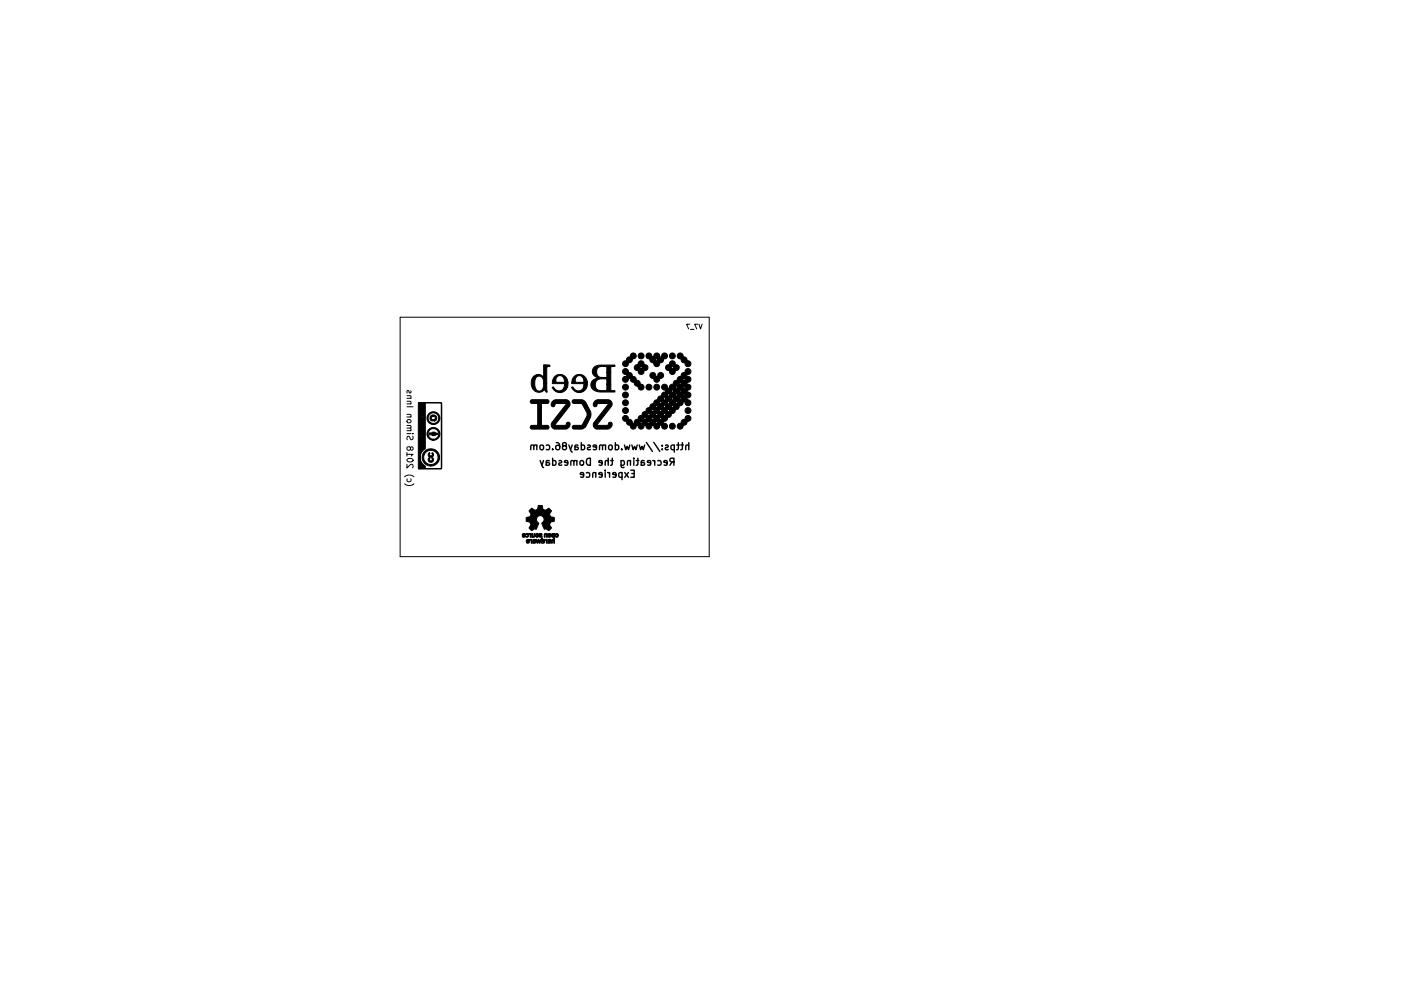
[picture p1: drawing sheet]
<svg xmlns="http://www.w3.org/2000/svg" width="297mm" height="210mm" viewBox="0 0 297 210" stroke-linecap="round" stroke-linejoin="round" font-family="sans-serif">
<g fill="none" stroke="#000" stroke-width=".21">
<path d="M84.8 67.3h65.6v50.8h-65.6zM146.2 68.8h-.6l.4 1M146.4 69.9h.7M148 68.8h-.7l.4 1M148.2 68.8l.3 1 .4-1M86.3 98.5v.8l.9-.8 .4 .2-.1 .5M86.3 96.4h1.3l-.4 .4M86.3 90.8l.8 .1-.1 .5M86.3 90.3h.8v.3l-.1 .2M86.3 87.9l.8 .1-.1 .5M86.3 85.1l.8 .1-.1 .5M86.3 84h.8l-.1 .5"/>
<path d="M86.3 96v.8M86.3 92h.8M86.3 91.4h.8M86.3 88.5h.8M86.3 86.3h1.3M86.3 85.7h.8M86.3 84.5h.8M86.3 97.4a.77 .77 0 0 1 1.3 .3 .74 .74 0 0 1-1.3-.1zM86.3 89.2l.6-.2 .2 .5-.2 .2h-.4l-.2-.2zM87 95l-.2-.2h-.4l-.1 .2 .1 .5h.4l.3-.7 .4 .1v.6h-.2l-.3-.2M87.1 82.9v.3l-.1 .2-.2-.1-.1-.4h-.4v.5M87.5 92h.1"/>
<path d="M87.5 92.6l.1 .5-.1 .1h-.4l-.3-.5-.3-.1-.2 .2v.5M85.8 102.6a1.49 1.49 0 0 0 2 0M85.8 101.2a1.49 1.49 0 0 1 2 0M86.3 101.6v.4l.2 .2 .6-.1v-.5"/>
</g>
<g fill="none" stroke="#000" stroke-width=".3">
<path d="M113.2 94.6l-.2-.2-.4 .1-.1 .9M113.8 94.6l-.2-.2-.3 .1-.1 .9M113.8 94.4v1M114.5 97.7l.5 1.4 .2 .1M114.5 94.6l.3-.2 .4 .2 .1 .5-.2 .2-.3 .1-.3-.1zM115.2 97.7l-.3 1M115.8 98.1h.5l.2 .3-.2 .3-.5-.1M115.8 94.5l.5-.1 .2 .3-.1 .6h-.6M116.5 97.8h-.6l-.1 .9M117.2 97.8l.4-.1 .3 .3-.2 .6h-.5M117.2 97.2v1.5M117.2 95.3v.1"/>
<path d="M118 93.9l.4 .1a1.01 1.01 0 0 1 0 1.4l-.5-.1-.1-.5 .3-.3 .4 .1 .2 .2M118.5 97.8l.4-.1 .2 .2-.1 .2-.5 .2v.3h.6M119.5 94.6l-.2 .2v.3l.2 .3 .5-.1 .1-.5-.1-.2-.7-.2 .1-.4 .4-.1 .2 .2 .1 .2-.3 .3M120.4 98.2l-.7-.1v-.3l.5-.1 .2 .2-.1 .7h-.6M120.6 94.4l.5 1.4 .2 .1M121.3 94.4l-.3 1M121.7 97.9l-.2-.2-.4 .1-.1 .9M121.9 94.8h.5l.2 .3-.2 .3-.5-.1M122.3 97.9l-.2-.2-.4 .1v.9M122.3 97.7v1M122.5 94.5h-.5l-.1 .9M123 97.9l.2-.2 .5 .2v.5l-.1 .2-.4 .1-.2-.1z"/>
<path d="M123.3 94.5l.4-.1 .3 .3-.2 .6h-.5M123.3 93.9v1.5M124.5 97.4l.7-.2v1.5a.78 .78 0 0 1-.8-.4 .78 .78 0 0 1 .1-.9zM124.6 94.5l.4-.1 .2 .2-.1 .2-.5 .2v.3h.6M126.5 94.9l-.7-.1v-.3l.5-.1 .2 .2-.1 .7h-.6M127.7 98.2l-.7-.1v-.3l.5-.1 .2 .2-.1 .7h-.6M127.8 94.6l-.3-.2-.3 .1-.1 .9M128.3 99.8v.1M128.4 94.6l-.2-.2-.4 .1v.9M128.4 94.4v1M129 97.9l-.3-.2-.3 .1-.1 .9M129 97.2v1.5"/>
<path d="M129.1 94.6l.2-.2 .5 .2v.5l-.1 .2-.4 .1-.2-.1zM129.5 97.7h.5M129.8 97.2v1.3l-.3 .2M130.5 94.5l.4-.1 .3 .3-.2 .6h-.5M130.5 93.9v1.5M131.7 97.7v1.2l.3 .3 .3-.1M131.7 97.8l.4-.1 .3 .3-.2 .6h-.5M131.8 95.3v.1M132.4 94.4l.3 1 .3-.7 .3 .7 .2-1M133.7 97.9l-.2-.2-.4 .1-.1 .9M133.7 97.7v1M133.7 99.8h.8v1.5h-.8"/>
<path d="M134 94.4l.3 1 .2-.7 .3 .7 .3-1M134.4 97.2v.2M134.4 97.7v1M134.9 97.7h.6M135.2 97.2v1.3l-.3 .2M135.5 94.4l.3 1 .3-.7 .3 .7 .3-1M136 98.1h.5l.2 .3-.2 .3-.5-.1M136.6 97.8h-.6v.9M137 93.8l1.3 2M138 98.2l-.8-.1 .1-.3 .4-.1 .3 .2-.1 .7h-.6M138.4 97.7l.4 .3M138.6 93.8l1.3 2"/>
<path d="M138.8 97.7v1M139.5 97.8l.4-.1 .3 .3-.2 .6h-.5M140.4 95.3v.1M140.4 94.5v.1M141.1 94.5l.4-.1 .2 .2-.1 .2-.5 .2v.3h.6M141.5 98.2l-.8-.1 .1-.3 .4-.1 .3 .2-.1 .7h-.6M142.5 98l-.5 .7M142.9 98l-.7-.1-.2-.2 .1-.3 .8-.2v1.5M143 94.5l-.5-.1-.2 .3 .1 .6h.6M143 94.4v1.5M143.5 94.4h.5M143.8 93.9v1.3l-.3 .2"/>
<path d="M144.3 94.4h.6M144.7 93.9v1.3l-.4 .2M146 94.6l-.2-.2-.3 .1-.1 .9M146 93.9v1.5M123.7 100.8l-.7-.2 .1-.3h.4l.2 .2v.7h-.6M124.3 100.3h.4l.3 .2-.1 .7h-.6M126.3 100.4l-.2-.1h-.4v1M126.3 100.3v1M127.7 100.8l-.7-.2v-.3h.5l.2 .2-.1 .7h-.6M128.3 100.3v1M128.8 100.3l.4 .2M129.2 100.3v1"/>
<path d="M130.6 100.8l-.7-.2 .1-.3h.4l.2 .2-.1 .7h-.5M131.9 100.3h-.4l-.3 .2 .1 .7h.6M131.9 100.3v1.5M132.5 100.3l.7 1M133.2 100.3l-.7 1M134 100.5h.5"/>
</g>
<g fill="#000" stroke="#000" stroke-width=".21">
<path d="M115.3 77.4l1.3 .1v.2l-.5 .1-.2 .3v3.3h-.6v-.3a.96 .96 0 0 0-.5-1.1 .96 .96 0 0 0-1.1 .1 2.25 2.25 0 0 0 .4 2.8l.3 .1a1.25 1.25 0 0 0 .9-1.6h.6l.1 1.8h-.1l-.5-.5a1.66 1.66 0 0 1-2 .3 1.66 1.66 0 0 1-.8-2 1.44 1.44 0 0 1 1-1.5 1.44 1.44 0 0 1 1.7 .6zM117.6 79.9l1-.4a1.69 1.69 0 0 1 1.8 1.6h-.7v-.1a.96 .96 0 0 0-.5-1.2 .96 .96 0 0 0-1.2 .2 .6 .6 0 0 0 .1 1.1h2.3a1.71 1.71 0 0 1-1.1 2.1 1.71 1.71 0 0 1-2.1-1.1h.2a1.23 1.23 0 0 0 1.5 .8 1.23 1.23 0 0 0 .8-1.5h-2.6l.1-.9zM121.7 79.9l1-.4a1.69 1.69 0 0 1 1.8 1.6h-.7v-.1a.96 .96 0 0 0-.4-1.2 .96 .96 0 0 0-1.2 .2 .6 .6 0 0 0 0 1.1h2.3a1.71 1.71 0 0 1-1.1 2.1 1.71 1.71 0 0 1-2.1-1.1h.2a1.23 1.23 0 0 0 1.5 .8 1.23 1.23 0 0 0 .8-1.5h-2.6l.2-.9zM126 77.9l1-.4h3.4v.2l-.9 .2v1.1h-.8l-.2-1.2h-1a1.2 1.2 0 0 0-1 1.4 1.2 1.2 0 0 0 1.6 .9h.6v-1.1h.8v2.5h-.8v-1.1h-1.4a1.3 1.3 0 0 0-1.1 1.6 1.3 1.3 0 0 0 1.7 .9h.4a.59 .59 0 0 0 .4-.9v-.5h.8v1.2l.9 .2v.3l-3.4-.1a1.49 1.49 0 0 1-1.5-.7 1.49 1.49 0 0 1 .1-1.6l1.2-.7a1.31 1.31 0 0 1-1.1-.8 1.31 1.31 0 0 1 .3-1.4zM132.2 78.4l.7-.2 .2 .2 .1 .4a.18 .18 0 0 0 0 .3 .18 .18 0 0 0 .3-.1l.4 .3 .2 .4a.17 .17 0 0 0 0 .2 .17 .17 0 0 0 .2 0l.5 .3v.5l.6 .1 .3 .5a.18 .18 0 0 0 0 .3 .18 .18 0 0 0 .3-.1h.1a.62 .62 0 0 1 .4 .8 .62 .62 0 0 1-.8 .4 .62 .62 0 0 1-.3-.8l-.7-.1-.2-.3v-.4l-.5-.1-.3-.5a.18 .18 0 0 0-.1-.3 .18 .18 0 0 0-.2 .1l-.2-.1v.5l-.4 .4h-.3l-.4-.3-.1-.4 .2-.4 .3-.1h.4v-.5h-.5l-.4-.3zM133 75.9l.4-.2a.18 .18 0 0 0 .3 0 .18 .18 0 0 0 0-.3l.1-.3 .3-.2 .6 .2 .1 .7-.2 .3h-.3a.18 .18 0 0 0-.3 0 .18 .18 0 0 0 .1 .3l-.2 .4-.4 .2a.2 .2 0 0 0-.3-.1 .2 .2 0 0 0 0 .3 .62 .62 0 0 1-.7 .6 .62 .62 0 0 1-.5-.8 .62 .62 0 0 1 .9-.4l-.1-.4zM134.7 77.6l.4-.2a.18 .18 0 0 0 .3 0 .18 .18 0 0 0-.1-.3l.2-.4 .5-.1 .4 .2 .1 .4a.18 .18 0 0 0 .1 .3 .18 .18 0 0 0 .2-.1l.5 .3-1.4 .1a.18 .18 0 0 0-.3 0 .18 .18 0 0 0 .1 .3v.2h.5v-.6h1.1v.6l-.5 .3a.2 .2 0 0 0-.3 0 .2 .2 0 0 0 0 .3 .62 .62 0 0 1-.7 .5 .62 .62 0 0 1-.4-.8h-.5l-.3-.2-.1-.5zM137.1 75.1l.7-.2 .3 .2 .1 .4a.18 .18 0 0 0 0 .3 .18 .18 0 0 0 .3-.1l.2 .1v-.6l.4-.3 .5 .1 .3 .5a.18 .18 0 0 0 0 .3 .18 .18 0 0 0 .2-.1l.2 .1v-.5l.4-.4 .5 .1 .3 .4-.1 .4-.4 .3h-1.8a.18 .18 0 0 0-.2 0 .18 .18 0 0 0 0 .3v.2h.5v-.5h1.1v.6l-.5 .3a.18 .18 0 0 0-.3-.1 .18 .18 0 0 0 .1 .3 .62 .62 0 0 1-.8 .6 .62 .62 0 0 1-.4-.9h-.6l-.3-.4v-.4h-.4l-.3-.2-.1-.5zM138 79.2l.6-.1 .3 .2 .1 .4a.18 .18 0 0 0 0 .2 .18 .18 0 0 0 .3 0h.2v-.4l.2-.3 .7-.1 .2 .3 .1 .4-.2 .3-.4 .2a.2 .2 0 0 0-.3-.1 .21 .21 0 0 0 .1 .4 .62 .62 0 0 1-.8 .5 .62 .62 0 0 1-.4-.9l-.4 .1-.4-.3-.1-.4zM142.1 76.7l.7-.1 .3 .3 .1 .3a.18 .18 0 0 0 0 .3 .18 .18 0 0 0 .3-.1l.4 .3-1.3 .1a.18 .18 0 0 0-.3 0 .18 .18 0 0 0 0 .3v.2h.5v-.6h1.1v.6l-.4 .3a.2 .2 0 0 0-.4 0 .2 .2 0 0 0 .1 .3 .62 .62 0 0 1-.8 .5 .62 .62 0 0 1-.4-.8l-.6-.1-.3-.4 .1-.5 .5-.2a.18 .18 0 0 0 .3 0 .18 .18 0 0 0-.1-.3zM143.8 75.1l.6-.2 .3 .2 .1 .4a.18 .18 0 0 0 0 .3 .18 .18 0 0 0 .3-.1l.4 .3 .2 .3a.18 .18 0 0 0 0 .3 .18 .18 0 0 0 .2 0h.1a.62 .62 0 0 1 .5 .7 .62 .62 0 0 1-.9 .5 .62 .62 0 0 1-.3-.9h-.6l-.3-.6a.18 .18 0 0 0 0-.2 .18 .18 0 0 0-.3 0l-.3-.1-.2-.3zM132.2 88.3l.7-.1 .2 .2 .1 .4a.18 .18 0 0 0 0 .2 .18 .18 0 0 0 .3 0l.4 .2 .2 .4a.18 .18 0 0 0 0 .3 .18 .18 0 0 0 .2-.1l.2 .1v-.4l.2-.3 .3-.2h.4v-.5l.5-.4a.18 .18 0 0 0 .3 0 .18 .18 0 0 0-.1-.2l.3-.5 .4-.1a.18 .18 0 0 0 .2 0 .18 .18 0 0 0 0-.3l.2-.4 .4-.1a.18 .18 0 0 0 .3 0 .18 .18 0 0 0-.1-.3l.2-.4 .4-.1a.18 .18 0 0 0 .3-.1 .18 .18 0 0 0-.1-.2l.2-.4 .4-.2a.18 .18 0 0 0 .3 0 .18 .18 0 0 0 0-.3l.1-.3 .5-.2a.18 .18 0 0 0 .2 0 .18 .18 0 0 0 0-.3l.2-.4 .4-.1a.18 .18 0 0 0 .3 0 .18 .18 0 0 0-.1-.3l.1-.2h-.5l-.3-.3-.1-.4 .2-.3 .6-.1 .4 .3v.5h.5v-.6l.6-.3a.18 .18 0 0 0 .2 0 .18 .18 0 0 0 0-.3l.2-.4 .4-.1a.18 .18 0 0 0 .3 0 .18 .18 0 0 0-.1-.3l.2-.4 .4-.1a.18 .18 0 0 0 .3-.1 .18 .18 0 0 0-.1-.2l.2-.4 .4-.2a.18 .18 0 0 0 .3 0 .18 .18 0 0 0-.1-.3l.2-.3 .3-.2 .6 .2 .1 .7-.2 .3h-.3a.18 .18 0 0 0-.3 .1 .18 .18 0 0 0 .1 .2l-.1 .2h.5l.3 .3-1.4 .1a.18 .18 0 0 0-.2 0 .18 .18 0 0 0 0 .3v.1h.5v-.5h1.1l.1 .2-.1 .4-.4 .3h-2.1v.5h.6v-.5h1.1v.5h.5l.3 .3h-3a.18 .18 0 0 0-.3 0 .18 .18 0 0 0 .1 .3l-.1 .2h.5v-.5h1.2v.2a.18 .18 0 0 0 0 .3 .18 .18 0 0 0 .3 0h.2v-.5l1.2 .1-.1 .5-.4 .2h-3.7v.5h.5v-.5h1.1v.5h.6v-.5h1.1v.5h.5l.3 .3h-4.9v.6h.5v-.6h1.1v.6h.5v-.6h1.2v.6h.5v-.6h1.1l.1 .4-.3 .4-5.3 .1a.18 .18 0 0 0-.3 0 .18 .18 0 0 0 .1 .3l-.1 .2h.6v-.5h1.1v.2a.18 .18 0 0 0 .1 .3 .18 .18 0 0 0 .2-.1l.2 .1v-.5h1.1v.5h.6v-.5h1.1v.5l.6 .1 .3 .6-.3 .3-.4 .2-.4-.3-.2-.3a.18 .18 0 0 0 0-.3 .18 .18 0 0 0-.2 0h-5.2v.5h.5v-.5h1.2v.5h.5v-.5h1.1v.5h.5v-.5h1.2l-.1 .6-.4 .3-5.3-.1v.5h.5v-.5h1.1v.5h.6v-.5h1.1v.5h.5v-.5h1.1v.6l-.4 .3-5.3-.1v.6h.5v-.6h1.1v.6h.5v-.6h1.2v.6h.5v-.6h1.1v.5l-.4 .4h-5.4v.5h.5v-.5h1.2v.5h.5v-.5h1.1v.5h.6v-.5h1.1v.5l-.3 .3h-5.5v.5h.5v-.5h1.2v.5h.5v-.5h1.1v.5h.5v-.5h1.2v.5l-.4 .3h-5.4v.6h.5v-.6h1.1v.6h.5v-.6h1.2v.6h.5v-.6h1.1v.6l.4-.1a.62 .62 0 0 1 .5 .8 .62 .62 0 0 1-.8 .4 .62 .62 0 0 1-.4-.8h-.2a.18 .18 0 0 0-.3 0 .18 .18 0 0 0 .1 .3l-.3 .4-.5 .1-.4-.3v-.5h-.5l-.1 .6-.6 .2-.5-.3v-.5h-.5l-.1 .6-.6 .2-.4-.3v-.5h-.6v.6l-.7 .2-.4-.3v-.5l-.6-.1-.3-.5a.18 .18 0 0 0 0-.3 .18 .18 0 0 0-.3 .1l-.3-.2-.2-.3z"/>
<path d="M89.2 92.4h.1v.2h-.2zM89.3 88.4l.3 .1-.3 .1zM89.5 92.4h.1v.2h-.1zM90.9 96.1l.2-.1 .1 .2a.29 .29 0 0 0 0 .4 .29 .29 0 0 0 .4 0 .29 .29 0 0 0 0-.4v-.1a.54 .54 0 0 1 .1 .9 .54 .54 0 0 1-.9-.2zM90.9 97.2l.2-.1 .1 .2a.29 .29 0 0 0 0 .4 .29 .29 0 0 0 .4 0 .29 .29 0 0 0 0-.5l.1-.1a.55 .55 0 0 1 .1 .8 .55 .55 0 0 1-.8 .1 .55 .55 0 0 1-.1-.8zM91 91.9l1.2-.2 .1 .4a.26 .26 0 0 1 0 .3 .26 .26 0 0 1-.3 0l-1-.1zM91.4 88.2a.72 .72 0 0 1 1.1 .1 .72 .72 0 0 1-.5 1.1l-.2-.2 .3-.3a.29 .29 0 0 0 .3-.3 .29 .29 0 0 0-.4-.2 .35 .35 0 0 0-.5 .1 .35 .35 0 0 0 .2 .5l-.1 .3a.63 .63 0 0 1-.2-1.1zM90 95.8a1.84 1.84 0 0 1 3 .5 1.84 1.84 0 0 1-1.6 2.6v-.3a1.51 1.51 0 0 0 1.2-2.3 1.51 1.51 0 0 0-2.6 0 1.51 1.51 0 0 0 1.3 2.3l.1 .3a1.83 1.83 0 0 1-1.7-1.1 1.83 1.83 0 0 1 .3-2zM90.9 87.8a1.36 1.36 0 0 1 2.2 .3 1.36 1.36 0 0 1-1.2 2v-.3a1.12 1.12 0 0 0 1-1.6 1.12 1.12 0 0 0-1.9-.1 1.12 1.12 0 0 0 .8 1.7h.1v.3a1.35 1.35 0 0 1-1.2-.8 1.35 1.35 0 0 1 .2-1.5zM90.9 91.1a1.36 1.36 0 0 1 2.3 .4 1.36 1.36 0 0 1-1.4 1.9v-.2a1.12 1.12 0 0 0 1.1-1.6 1.12 1.12 0 0 0-1.9-.2 1.12 1.12 0 0 0 .7 1.8h.1v.2a1.35 1.35 0 0 1-1.2-.9 1.35 1.35 0 0 1 .3-1.4zM88.7 85.4h4.6l.3 .2v13.8l-.1 .1v-14h-3.3v9.7a2.09 2.09 0 0 0 0 3.7v.5l3.3 .1h-4.5v-6.7h.8v-.9l-.3-.1 .3-.2v-.2l-.6 .3 .1-2.3-.2-.2 .2-.1a.29 .29 0 0 0 .1 .4 .29 .29 0 0 0 .4-.2 .29 .29 0 0 0-.3-.4l.2 .3-.2 .1a.32 .32 0 0 0-.1-.3 .32 .32 0 0 0-.4 0v-.1l.7-.3a.46 .46 0 0 0-.6-.5l-.1 .1a.37 .37 0 0 1 0 .6v.5l.2 .3v2.1h-.2v.2l.8 .2v.4l-.1-.3h-.4l-.3 .2v7.1h-.3v-.2zM112.5 84.9l.2-.1h3.5a.41 .41 0 0 1 .2 .4 .41 .41 0 0 1-.3 .4h-1.3v4.7h1.3l.3 .3-.2 .4h-.8h-2.7l-.2-.2-.1-.3 .3-.2h1.3v-4.7h-1.3a.41 .41 0 0 1-.2-.7z"/>
<path d="M117.2 85.1l.6-.3h2.3a.98 .98 0 0 1 .8 .8 .98 .98 0 0 1-.5 1l-2.7 3.6h2.2l.5-.6a.57 .57 0 0 1 .5 .4 .57 .57 0 0 1-.3 .7l-.7 .3h-2.3a1.05 1.05 0 0 1-.7-.9 1.05 1.05 0 0 1 .5-1l2.4-3a.24 .24 0 0 0 .2-.2 .24 .24 0 0 0-.1-.3h-2l-.4 .6-.3 .1a.62 .62 0 0 1-.4-.6 .62 .62 0 0 1 .4-.6zM121.4 84.9l1.9-.1 .6 .3 1.2 2.1 .2 .6-.2 .8-1.1 2.1-.6 .3h-1.8a.46 .46 0 0 1-.1-.6 .46 .46 0 0 1 .6-.1l1.4-.2 .9-1.8 .1-.5-1.1-2.1-1.8-.1-.3-.3zM126.1 85.1l.6-.3h2.3a.98 .98 0 0 1 .8 .8 .98 .98 0 0 1-.5 1l-2.7 3.6h2.2l.5-.6a.57 .57 0 0 1 .6 .4 .57 .57 0 0 1-.4 .7l-.6 .3h-2.4a1.05 1.05 0 0 1-.7-.9 1.05 1.05 0 0 1 .5-1l2.4-3a.24 .24 0 0 0 .3-.2 .24 .24 0 0 0-.1-.3h-2.1l-.4 .6-.3 .1a.62 .62 0 0 1-.4-.6 .62 .62 0 0 1 .4-.6zM144.6 89.2l.4-.2a.18 .18 0 0 0 .3 0 .18 .18 0 0 0-.1-.3l.2-.4 .3-.1 .6 .1 .1 .7-.2 .3-.3 .1a.18 .18 0 0 0-.3 0 .18 .18 0 0 0 .1 .3l-.2 .3-.4 .2a.2 .2 0 0 0-.3 0 .2 .2 0 0 0 0 .3 .62 .62 0 0 1-.7 .5 .62 .62 0 0 1-.5-.8 .62 .62 0 0 1 .9-.3l-.1-.4zM110.8 113.3a.33 .33 0 0 1 .4-.1 .33 .33 0 0 1 .2 .3l-.4-.2-.1 .2a.31 .31 0 0 1 .5 .1 .31 .31 0 0 1-.1 .4 .31 .31 0 0 1-.4 0l-.2-.1 .5-.2h-.5zM111.4 113.3a.39 .39 0 0 1 .6 0 .39 .39 0 0 1 0 .6 .39 .39 0 0 1-.6 0l.1-.1a.26 .26 0 0 0 .4-.1 .26 .26 0 0 0-.3-.3zM111.7 114.5a.33 .33 0 0 1 .4 0 .33 .33 0 0 1 .1 .3l-.3-.2-.1 .2a.31 .31 0 0 1 .4 .1 .31 .31 0 0 1-.1 .4 .31 .31 0 0 1-.4-.1v-.2l.3 .1 .1-.2h-.5zM112.1 113.2h.5v.8h-.2v-.6zM112.2 114.5l.6-.1v.9h-.2v-.6zM113 114.5h.6l-.5 .2 .4 .1 .1 .2h-.5l.1 .1 .4-.1-.1 .2-.6 .1zM112.7 113.2h.2l.1 .6 .2-.1v-.5h.2v.4a.43 .43 0 0 1-.2 .4 .43 .43 0 0 1-.5 0zM113.7 113.2a.34 .34 0 0 1 .3 0 .34 .34 0 0 1 .2 .4l-.2-.1a.17 .17 0 0 0-.2-.1 .17 .17 0 0 0 0 .3 .17 .17 0 0 0 .2 0v-.1a.22 .22 0 0 1 .2 .3 .22 .22 0 0 1-.3 .1l-.3-.2z"/>
<path d="M112.5 108l.2-.2 .7 .5 .6-.3 .1-.8h.9l.1 .8 .6 .3 .7-.5a.56 .56 0 0 1 .3 .9 .68 .68 0 0 0 0 .9 .68 .68 0 0 0 .8 .2 .55 .55 0 0 1-.3 .9 .71 .71 0 0 0-.6 .5 .71 .71 0 0 0 .3 .8 .55 .55 0 0 1-.8 .4l-.4-.2-.3 .1-.5-1.2a.83 .83 0 0 0 .5-1.1 .83 .83 0 0 0-1.1-.5 .83 .83 0 0 0-.5 1l.3 .4a1.26 1.26 0 0 1-.3 1.2l-.1 .2a.44 .44 0 0 0-.8 .2 .67 .67 0 0 1-.7-.5 .74 .74 0 0 0 .3-.9 .74 .74 0 0 0-.8-.5h-.1a.55 .55 0 0 1 .4-.9 .68 .68 0 0 0 .6-.6 .68 .68 0 0 0-.4-.7zM113.6 114.4h.2l.1 .6 .2-.6h.1l.2 .5 .2-.5h.1l-.2 .9h-.2l-.1-.6-.2 .6-.1-.1zM114.3 113.3a.32 .32 0 0 1 .4-.1 .32 .32 0 0 1 .2 .4 .32 .32 0 0 1-.4 .1l.5 .2a.32 .32 0 0 1-.5 .1 .32 .32 0 0 1-.1-.5l.3-.1h-.3zM114.8 114.1h.2v.4h.4l.1 .4-.2-.1a.19 .19 0 0 0-.3-.1 .19 .19 0 0 0 0 .3 .19 .19 0 0 0 .3 0l.2-.1-.2 .3-.5 .1zM115.5 113.2h.5v.8h-.1v-.4a.17 .17 0 0 0-.2-.2 .17 .17 0 0 0-.1 .2v.4h-.2zM115.5 114.5l.5-.1v.9h-.2v-.3a.33 .33 0 0 0-.3-.5zM116.3 113.3l.3-.1 .2 .3-.3-.2-.2 .2h.4a.27 .27 0 0 1 .1 .4 .27 .27 0 0 1-.3 .1l-.3-.1 .5-.2h-.5zM116.3 114.5h.5l-.4 .2 .4 .2v.1l-.4-.1 .1 .2 .3-.1v.2l-.6 .1zM117 113.2h.6v.4h-.2a.2 .2 0 0 0-.3-.2 .2 .2 0 0 0-.1 .3 .2 .2 0 0 0 .3 .1l.3-.2v1.7l-.2-.1-.1-.6-.2 .1v.6h-.2l.1-.7 .1-.2 .3 .1v-.6a.4 .4 0 0 1-.5-.1 .4 .4 0 0 1 .1-.6zM117.8 113.3l.4-.1 .2 .4h-.2a.19 .19 0 0 0-.3-.1 .19 .19 0 0 0 0 .3 .19 .19 0 0 0 .3 0v-.2h.2a.37 .37 0 0 1-.5 .4 .37 .37 0 0 1-.2-.6z"/>
<circle cx="135.9" cy="75.5" r=".62"/>
<circle cx="142.6" cy="75.5" r=".62"/>
<circle cx="92.6" cy="92.1" r=".18"/>
<circle cx="132.6" cy="83.8" r=".62"/>
<circle cx="132.6" cy="85.5" r=".62"/>
<circle cx="132.6" cy="82.1" r=".62"/>
<circle cx="132.6" cy="87.1" r=".62"/>
<circle cx="137.6" cy="82.1" r=".62"/>
<circle cx="139.2" cy="82.1" r=".62"/>
<circle cx="142.6" cy="90.4" r=".62"/>
<circle cx="145.9" cy="87.1" r=".62"/>
</g>
</svg>
